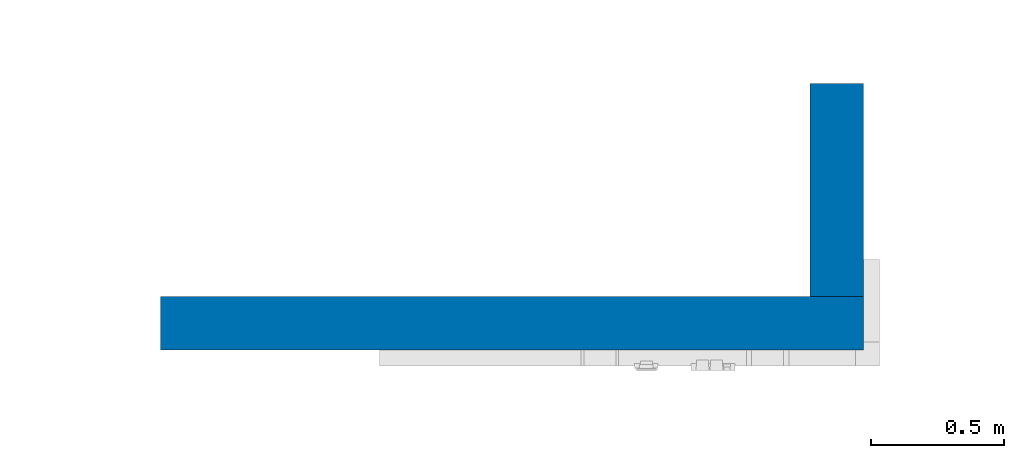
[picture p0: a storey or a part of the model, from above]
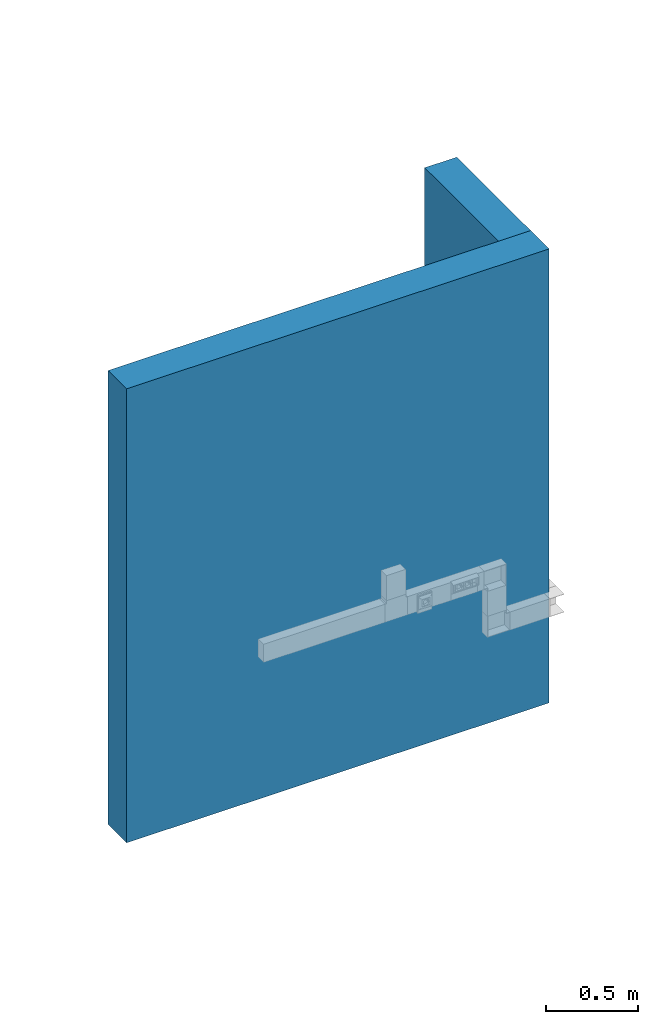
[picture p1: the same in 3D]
Properties of the parts of a building model (IFC2X3)

# File
Description: ViewDefinition [CoordinationView_V2.0]
File name: Номер проекта
Time: 2022-09-15T02:01:46
Written by: The EXPRESS Data Manager Version 5.02.0100.07 : 28 Aug 2013
Made in: 20190225_1515(x64) - Exporter 19.2.10.7 - Альтернативный интерфейс 19.2.10.7
Comment: STEP Physical File produced by: The EXPRESS Data Manager Version 5.02.0100.07 : 28 Aug 2013 * Module: EDMstepFileFactory/EDMstandAlone * Creation date: Thu Sep 15 02:01:46 2022 * Host: Dell * Database: C:\Users\6EDA~1\AppData\Local\Temp\{0415DEBD-7B85-45DE-92FF-0FBF76A48F47}\ifc * Database version: 5507 * Database creation date: Thu Sep 15 02:01:37 2022 * Schema: IFC2X3 * Model: DataRepository.ifc * Model creation date: Thu Sep 15 02:01:37 2022 * Header model: DataRepository.ifc_HeaderModel * Header model creation date: Thu Sep 15 02:01:37 2022 * EDMuser: sdai-user * EDMgroup: sdai-group * License ID and type: 5605 : Permanent license. Expiry date: * EDMstepFileFactory options: 020000

# IfcProject, Номер проекта
LongName: Наименование проекта; Phase: П

# IfcSite, Default
RefLatitude: 55, 44, 57, 789001; RefLongitude: 37, 38, 4, 304809; RefElevation: 0 mm

# IfcBuilding, Наименование здания
LongName: Наименование здания
Pset_BuildingCommon - NumberOfStoreys: 1

# IfcBuildingStorey, Этаж 01
In: Наименование здания
LongName: Этаж 01; Elevation: 0 mm

# IfcBuildingElementProxy: 1 модуль, КНС_СуппортДляМонтажаЭУИСерииVivaНаDIN-рейкуИлиМонтажнуюПлату_DKC:1 модуль:315350
In: Этаж 01
Type - Material: DKC_Пластик_СерыйМеталлик
Pset_BuildingElementProxyCommon - Reference: 1 модуль

# IfcBuildingElementProxy: 2 модуля (2)
In: Этаж 01
Type - Material: DKC_Пластик_Белый
Pset_BuildingElementProxyCommon - Reference: 2 модуля
Name
КНС_КаркасНа2Модуля(одноместный)БезЛапок_DKC:2 модуля:319769
КНС_РамкаДляМонтажаЭУИBravaВКоробкиPDD-N60_DKC:2 модуля:320897

# IfcBuildingElementProxy: 45х45 (7)
In: Этаж 01
Type - Material: DKC_Пластик_Белый
Pset_BuildingElementProxyCommon - Reference: 45х45
Name (КНС_РамкаСуппорт_ILC_DKC:45х45:...)
333314
333315
333316
333317
333318
333319
333320

# IfcBuildingElementProxy: SDN1, КНС_КоробкаРаспределительнаяSDN_ILC_DKC:SDN1:278972
In: Этаж 01
Type - Material: DKC_Пластик_Белый
Pset_BuildingElementProxyCommon - Reference: SDN1

# IfcBuildingElementProxy: SDN1 Коробка 151х151х60, КНС_КоробкаРаспределительнаяSDN_ILC_DKC:SDN1 Коробка 151х151х60:333378
In: Этаж 01
Type - Material: DKC_Пластик_Белый
Pset_BuildingElementProxyCommon - Reference: SDN1 Коробка 151х151х60

# IfcBuildingElementProxy: SDN2, КНС_КоробкаРаспределительнаяSDN_ILC_DKC:SDN2:333386
In: Этаж 01
Type - Material: DKC_Пластик_Белый
Pset_BuildingElementProxyCommon - Reference: SDN2

# IfcBuildingElementProxy: SDN3, КНС_КоробкаРаспределительнаяSDN_ILC_DKC:SDN3:333396
In: Этаж 01
Type - Material: DKC_Пластик_Белый
Pset_BuildingElementProxyCommon - Reference: SDN3

# IfcBuildingElementProxy: TA-GN 60x... (6)
In: Этаж 01
Type - Material: DKC_Пластик_Белый
Pset_BuildingElementProxyCommon - Reference: TA-GN 60x...
Name (КНС_РамкаДляВводаRQM_ILC_DKC:TA-GN 60x...:...)
284893
347399
347414
347427
347430
347433

# IfcBuildingElementProxy: Белый (3)
In: Этаж 01
Type - Material: DKC_Пластик_Белый
Pset_BuildingElementProxyCommon - Reference: Белый
Name (КНС_СиловыеЭлектрическиеРозеткиШтекерныеСЗаземлениемИСоШторками_DKC:Белый:...)
312627
315782
321916

# IfcBuildingElementProxy: Категория 5e, КНС_КомпьютерныеРозетки_DKC:Категория 5e:315349
In: Этаж 01
Type - Material: DKC_Пластик_Серо-черный, DKC_Пластик_Белый
Pset_BuildingElementProxyCommon - Reference: Категория 5e

# IfcBuildingElementProxy: Лого, Лого:Лого:288632
In: Этаж 01
Type - Material: DKC_КрасныйЛого
Pset_BuildingElementProxyCommon - Reference: Лого

# IfcBuildingElementProxy: Рамка суппорт PDA-N_DKC (4)
In: Этаж 01
Type - Material: DKC_Пластик_Белый
Pset_BuildingElementProxyCommon - Reference: Рамка суппорт PDA-N_DKC
Name (КНС_РамкаСуппортPDA-N_ILC_DKC:Рамка суппорт PDA-N_DKC:...)
274721
305040
333441
333447

# IfcBuildingElementProxy: Распределительная коробка (Италия) 151х151х75, КНС_КоробкаРаспределительнаяSDN_ILC_DKC:Распределительная коробка (Италия) 151х151х75:333410
In: Этаж 01
Type - Material: DKC_Пластик_Белый
Pset_BuildingElementProxyCommon - Reference: Распределительная коробка (Италия) 151х151х75

# IfcBuildingElementProxy: Серия "Brava" (7)
In: Этаж 01
Type - Material: DKC_Пластик_Белый
Pset_BuildingElementProxyCommon - Reference: Серия "Brava"
Name (КНС_РамкаСуппорт_ILC_DKC:Серия "Brava":...)
333300
333301
333302
333303
333304
333305
333306

# IfcBuildingElementProxy: Серия "Viva" (8)
In: Этаж 01
Type - Material: DKC_Пластик_Белый
Pset_BuildingElementProxyCommon - Reference: Серия "Viva"
Name (КНС_РамкаСуппорт_ILC_DKC:Серия "Viva":...)
278165
308161
333226
333241
333244
333247
333253
333269

# IfcBuildingElementProxy: Текст модели:100 мм Arial (117)
In: Этаж 01
Pset_BuildingElementProxyCommon - Reference: 100 мм Arial

# IfcBuildingElementProxy: Текст модели:150 мм Arial (21)
In: Этаж 01
Pset_BuildingElementProxyCommon - Reference: 150 мм Arial

# IfcBuildingElementProxy: Текст модели:300 мм Arial (5)
In: Этаж 01
Pset_BuildingElementProxyCommon - Reference: 300 мм Arial

# IfcBuildingElementProxy: Текст модели:600 мм Arial
In: Этаж 01
Pset_BuildingElementProxyCommon - Reference: 600 мм Arial

# IfcDistributionPort (18)
Description: Flow; FlowDirection: SOURCEANDSINK
Name
2 x InPort_304634
2 x OutPort_318471
OutPort_304635
InPort_304635
2 x OutPort_322714
2 x InPort_318360
2 x OutPort_318362
InPort_318361
3 x InPort_322144
OutPort_322644
OutPort_322832

# IfcFlowFitting: Заглушка торцевая LAN_DKC (16)
In: Этаж 01
Type - Material: DKC_Пластик_Белый
Pset_DistributionFlowElementCommon - Reference: Заглушка торцевая LAN_DKC
Name (КНС_ЗаглушкаТорцеваяLAN_ILC_DKC:Заглушка торцевая LAN_DKC:...)
324811
345540
345554
345557
345560
345563
345566
345569
345572
345575
345578
345581
345584
345587
345590
345593

# IfcFlowFitting: Тройник/отвод (17)
In: Этаж 01
Type - Material: DKC_Пластик_Белый
Pset_DistributionFlowElementCommon - Reference: Тройник/отвод
Name (КНС_ТройникNTAN_ILC_DKC:Тройник/отвод:...)
267829
322144
344276
344289
344292
344295
344298
344301
344304
344307
344310
344313
344316
344319
344322
344325
344328

# IfcFlowFitting: Угол внешний_DKC (23)
In: Этаж 01
Type - Material: DKC_Пластик_Белый
Pset_DistributionFlowElementCommon - Reference: Угол внешний_DKC
Name (КНС_УголВнешний_ILC_DKC:Угол внешний_DKC:...)
266585
318362
341997
342000
342003
342012
342015
342914
342915
342916
342917
342918
342919
342920
342921
342922
342923
342924
342925
342926
342927
342928
342929

# IfcFlowFitting: Угол внутренний_DKC (21)
In: Этаж 01
Type - Material: DKC_Пластик_Белый
Pset_DistributionFlowElementCommon - Reference: Угол внутренний_DKC
Name (КНС_УголВнутренний_ILC_DKC:Угол внутренний_DKC:...)
265538
330288
341270
341273
341276
341285
341288
341414
341416
341417
341418
341420
341421
341422
341423
341424
341425
341426
341427
341428
341429

# IfcFlowFitting: Угол плоский NPAN_DKC (19)
In: Этаж 01
Type - Material: DKC_Пластик_Белый
Pset_DistributionFlowElementCommon - Reference: Угол плоский NPAN_DKC
Name (КНС_УголПлоский NPAN_ILC_DKC:Угол плоский NPAN_DKC:...)
260847
304635
318471
331229
339964
339977
339980
339983
339986
339989
339992
339995
339998
340001
340004
340007
340010
340013
340016

# IfcFlowSegment: Кабельный лоток с соединительными деталями:Короб с крышкой с плоской основой, TA-EN (8)
In: Этаж 01
Type - PredefinedType: CABLETRAYSEGMENT
Pset_DistributionFlowElementCommon - Reference: Короб с крышкой с плоской основой, TA-EN
Name (Кабельный лоток с соединительными деталями:Короб с крышкой с плоской основой, TA-EN:...)
285054
304634
318360
318361
322644
322714
322832
322967

# IfcFlowSegment: Кабельный лоток с соединительными деталями:Короб с крышкой, с направляющими для установки разделителей, TA-GN (8)
In: Этаж 01
Type - PredefinedType: CABLETRAYSEGMENT
Pset_DistributionFlowElementCommon - Reference: Короб с крышкой, с направляющими для установки разделителей, TA-GN
Name (Кабельный лоток с соединительными деталями:Короб с крышкой, с направляющими для установки разделителей, TA-GN:...)
259512
336370
336385
336388
336391
336394
336397
336400

# IfcWallStandardCase: Базовая стена:Типовой - 200мм (2)
In: Этаж 01
Type - PredefinedType: STANDARD; Material: <Unnamed> 200 mm
Pset_WallCommon - Reference: Типовой - 200мм; LoadBearing: no; ExtendToStructure: no; IsExternal: yes
Name (Базовая стена:Типовой - 200мм:...)
304794
317787
